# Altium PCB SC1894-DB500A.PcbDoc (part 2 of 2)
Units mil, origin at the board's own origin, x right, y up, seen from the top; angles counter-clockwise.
Board outline 1800 x 1000 mil, 4 copper layers (L1 TOP, L2 GND, L3 PWR, L4  BOT), stack 35.4 mil thick; 141 components, 89 nets, 320 pads, 589 vias.

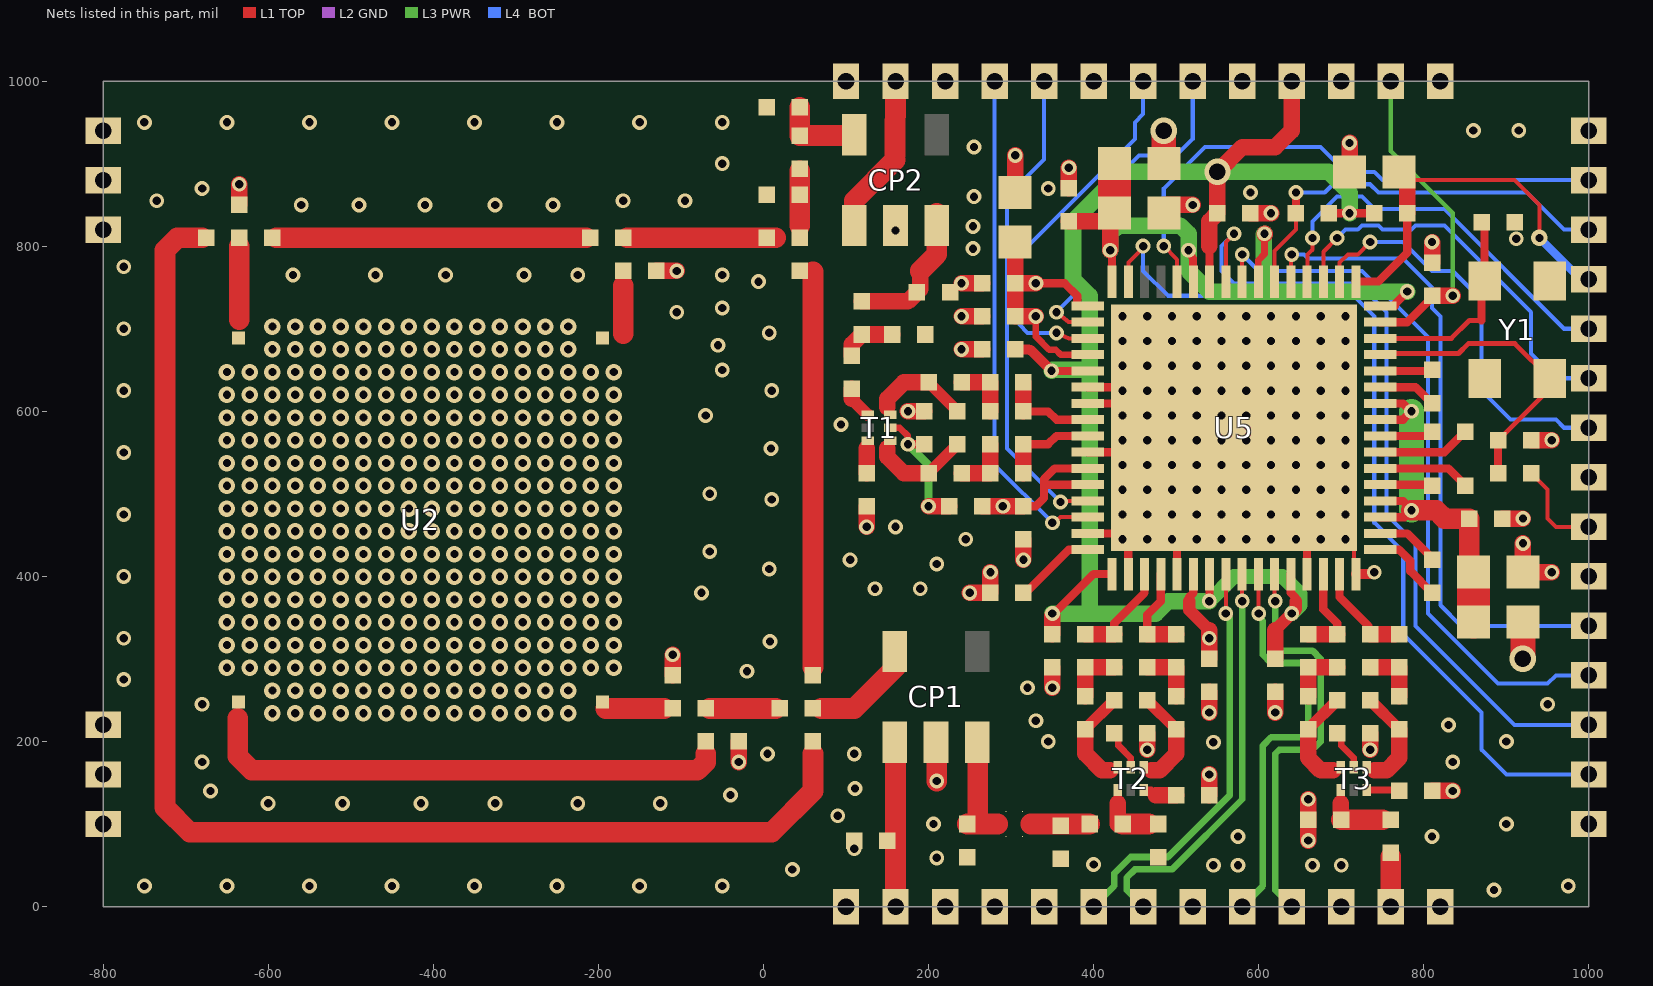
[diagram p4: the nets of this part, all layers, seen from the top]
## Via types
v1: diameter 20, hole 10, L1 TOP to L4  BOT, tented both sides, 308 vias
v2: diameter 18/18/18/18 (per signal layer), hole 10, L1 TOP to L4  BOT, tented both sides, 177 vias
v3: diameter 18/18/18/18 (per signal layer), hole 10, L1 TOP to L4  BOT, 100 vias
v4: diameter 32/32/32/32 (per signal layer), hole 20, L1 TOP to L4  BOT, tented both sides, 3 vias
v5: diameter 20/20/20/20 (per signal layer), hole 10, L1 TOP to L4  BOT, tented both sides, 1 vias

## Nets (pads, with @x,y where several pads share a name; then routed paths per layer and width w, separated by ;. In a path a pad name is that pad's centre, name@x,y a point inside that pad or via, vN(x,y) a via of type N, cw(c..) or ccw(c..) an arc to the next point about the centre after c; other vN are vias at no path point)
+1.8V: C6.1 C8.1 C9.1 C12.1 C31.1 C34.1 FT1.2 FT2.1 FT3.1 P30.1 U5.1 U5.4 U5.11 U5.12 U5.22 U5.47 | length 1125
  L1 TOP w5: C8.1@810,740 C8.1@812.05,740
  L1 TOP w8: v2(330,715) 330,690.58 346,674.58 354,674.58 360,668.58 U5.4@392.83,668.58
  L1 TOP w10: C31.1@315,485 330,485 340,495 340,511.1 ; v2(330,755) 365,755 380,740 380,727.64 U5.1@392.83,727.64 ; U5.12@392.83,511.1 340,511.1 ; U5.11@392.83,530.79 352.8,530.79 340,517.99 340,511.1 ; 515.79,370 515.79,375 520.79,380 U5.22@520.79,402.83 ; U5.47@747.17,707.95 780,707.95 C8.1@812.05,740
  L1 TOP w15: 515.79,370 515.79,359.21 540,335
  L1 TOP w20: FT3.1@265,485 v2(290,485) C31.1@315,485 ; C6.1@305,805 C9.1@305,755 ; v2(330,715) C12.1@305,715 C9.1@305,755 ; v2(330,755) C9.1@305,755 ; C34.1@540,300 v2(540,325) 540,335 ; C8.1@812.05,740 v2(835,740)
  L1 TOP w30: FT1.2@485,900 v4(485,940) ; v4(920,300) FT2.1@920,345
  L3 PWR w5: P30.1@760,1000 760,915 835,840 v2(835,740)
+3.3V: C3.2 C14.1 C33.1 C35.1 P32.1 R1.2 R2.1 U5.5 U5.17 U5.23 U5.28 U5.58 | length 2007.7
  L1 TOP w10: v2(349,649) 349.1,648.9 U5.5@392.83,648.9 ; v2@350,352.49 v2(350,355) 352.17,355 400,402.83 U5.17@422.36,402.83 ; v2(540,370) 540.47,370.47 U5.23@540.47,402.83 ; 540,800 540.47,799.53 U5.58@540.47,757.17 ; U5.28@638.9,402.83 638.9,380 645,373.9 645,370 ; R1.2@685,840 v2(710,840) R2.1@740,840
  L1 TOP w12: C14.1@305,675 321.34,675 322.17,674.17 323.83,674.17 v2(349,649)
  L1 TOP w15: 620,335 v2(640,355) 645,360 645,370
  L1 TOP w20: C33.1@350,330 v2@350,352.49 ; 540,800 540,830 C3.2@550,840 v4(550,890) 580,920 620,920 640,940 P32.1@640,1000 ; C35.1@620,300 620,335
  L3 PWR w18: v2(540,370) 570,400 628.75,400 650,378.75 650,365 v2(640,355)
  L3 PWR w20: v2(349,649) 350,650 395,650 ; v2(350,355) 395,355 ; v2(540,370) 490,370 475,355 395,355 ; v2(710,840) 710,865 685,890 v4(550,890) 435,890 375,830 375,760 395,740 395,650 ; 395,355 395,650
ADCIN0N: P7.1 U5.25 | length 495.6
  L1 TOP w5: U5.25@579.84,402.83 579.84,370 v2(580,370)
  L3 PWR w8: P7.1@460,0 440,20 440,35 450,45 495,45 580,130 v2(580,370)
ADCIN0P: P6.1 U5.24 | length 499.8
  L1 TOP w5: v2(560,355) 560.16,355 U5.24@560.16,402.83
  L3 PWR w8: P6.1@400,0 425,25 425,40 445,60 490,60 565,135 565,350 v2(560,355)
ADCIN1N: P10.1 U5.27 | length 504.3
  L1 TOP w5: U5.27@619.21,402.83 619.21,370 v2(620,370)
  L3 PWR w8: v2(620,370) 620,315 625,310 665,310 675,300 675,200 665,190 625,190 620,185 620,20 P10.1@640,0
ADCIN1P: P9.1 U5.26 | length 507.3
  L1 TOP w5: U5.26@599.53,402.83 599.53,355 v2(600,355)
  L3 PWR w8: P9.1@580,0 605,25 605,195 615,205 655,205 660,210 660,290 655,295 615,295 605,305 605,345 v2(600,355)
DGPIN0: P15.1 U5.63 | length 1104.3
  L1 TOP w5: U5.63@442.05,757.17 442.05,780 460,797.95 v2(460,800)
  L4  BOT w5: v2(460,800) 460,770 490,740 715,740 740,715 740,465 775,430 775,330 870,235 870,190 900,160 P15.1@1000,160
DGPIN1: P17.1 U5.56 | length 868.8
  L1 TOP w5: U5.56@579.84,757.17 579.84,790 v2(580,790)
  L4  BOT w5: v2(580,790) 600,770 725,770 805,690 805,355 890,270 950,270 960,280 P17.1@1000,280
EXTCLKIN: C15.2 P20.1 | length 117.4
  L1 TOP w5: C15.2@930,525 950,505 950,470 960,460 P20.1@1000,460
GND: C1.2 C2.1 C3.1 C4.2 C6.2 C8.2 C9.2 C10.2 C11.2 C12.2 C14.2 C26.1 C28.1 C29.2 C30.2 C31.2 C33.2 C34.2 C35.2 C36.2 C38.2 C40.2 C41.1 C45.2 C46.2 C47.2 CP1.2 CP2.2 P1.1 P3.1 P4.1 P5.1 P8.1 P11.1 P13.1 P14.1 P19.1 P21.1 P28.1 P29.1 P31.1 P33.1 P36.1 P39.1 P41.1 P42.1 P43.1 P44.1 P45.1 P46.1 P47.1 R12.1 R13.1 R15.1 R21.2 R23.2 R25.2 R27.2 R98.1 R99.1 R104.1 R105.1 U5.6 U5.7 U5.10 U5.15 U5.18 U5.21 U5.29 U5.32 U5.65 Y1.2 Y1.4 | length 2356.1
  L1 TOP w5: v3(705,445) 715.47,445 715.47,405 U5.32@717.64,402.83
  L1 TOP w10: U5.15@392.83,452.05 U5.65@442.05,452.05 ; U5.10@392.83,550.47 U5.65@442.05,550.47 ; U5.7@392.83,609.53 U5.65@570,609.53 ; U5.6@392.83,629.21 555,629.21 570,629.21 U5.65@570,609.53 ; U5.18@442.05,402.83 U5.65@442.05,452.05 ; U5.21@501.1,402.83 U5.65@501.1,452.05 ; U5.29@658.58,402.83 658.58,580 U5.65@570,580 ; U5.65@442.05,452.05 U5.65@501.1,452.05 ; U5.65@442.05,452.05 U5.65@442.05,550.47 ; U5.65@442.05,550.47 U5.65@501.1,550.47 ; U5.65@501.1,452.05 U5.65@501.1,550.47 ; U5.65@501.1,550.47 501.1,580 U5.65@570,580 ; U5.65@501.1,550.47 570,550.47 U5.65@570,580 ; U5.65@570,580 U5.65@570,609.53
  L1 TOP w12: U5.32@717.64,402.83 737.83,402.83 v2(740,405)
  L1 TOP w20: R98.1@-635,850 v2(-635,875) ; R105.1@-130,770 v2(-105,770) ; R104.1@-110,280 v2(-110,305) ; v2(-30,175) R99.1@-30,200 ; v2(125,460) C40.2@125,485 ; v2(175,600) C26.1@195,600 ; v2(240,675) C14.2@265,675 ; v2(240,715) C12.2@265,715 ; v2(240,755) C9.2@265,755 ; v2(250,380) R12.1@275,380 v2(275,405) ; C6.2@305,865 v2(305,910) ; v2(315,420) C31.2@315,445 ; v2(350,265) C33.2@350,290 ; C4.2@370,870 v2(370,895) ; v2(465,190) C28.1@465,210 ; C2.1@485,840 485,850 v2(520,850) ; C38.2@540,135 v2(540,160) ; v2(540,235) C34.2@540,260 ; C3.1@590,840 v2(615,840) ; v2(620,235) C35.2@620,260 ; v2(660,80) C45.2@660,105 v2(660,130) ; C1.2@710,890 v2(710,925) ; v2(735,190) C36.2@735,210 ; C41.1@810,140 v2(835,140) ; C8.2@810,780 v2(810,805) ; C29.2@895,470 v2(920,470) ; v2(920,440) C30.2@920,405 v2(955,405) ; C11.2@930,565 v2(955,565)
  L1 TOP w25: v2(210,152) CP1.2@210,210
  L2 GND w20: P1.1@100,0 100,1.81 P1.1@100.69,2.5 ; P3.1@219.7,2.5 220,2.2 P3.1@220,0 ; P31.1@700,999.24 P31.1@701.74,997.5 ; P13.1@820,2.33 P13.1@820.17,2.5
  L3 PWR w20: P1.1@100,0 100,1.94 P1.1@100.56,2.5 ; P3.1@220,0 P3.1@220,2.5
  other v1: -594.79,234.09 -567.23,234.09 -539.67,234.09 -512.11,234.09 -484.55,234.09 -456.99,234.09 -429.43,234.09 -401.87,234.09 -374.32,234.09 -346.76,234.09 -319.2,234.09 -291.64,234.09 -264.08,234.09 -236.52,234.09 -594.79,261.65 -567.23,261.65 -539.67,261.65 -512.11,261.65 -484.55,261.65 -456.99,261.65 -429.43,261.65 -401.87,261.65 -374.32,261.65 -346.76,261.65 -319.2,261.65 -291.64,261.65 -264.08,261.65 -236.52,261.65 -649.91,289.21 -622.35,289.21 -594.79,289.21 -567.23,289.21 -539.67,289.21 -512.11,289.21 -484.55,289.21 -456.99,289.21 -429.43,289.21 -401.87,289.21 -374.32,289.21 -346.76,289.21 -319.2,289.21 -291.64,289.21 -264.08,289.21 -236.52,289.21 -208.96,289.21 -181.4,289.21 -649.91,316.77 -622.35,316.77 -594.79,316.77 -567.23,316.77 -539.67,316.77 -512.11,316.77 -484.55,316.77 -456.99,316.77 -429.43,316.77 -401.87,316.77 -374.32,316.77 -346.76,316.77 -319.2,316.77 -291.64,316.77 -264.08,316.77 -236.52,316.77 -208.96,316.77 -181.4,316.77 -649.91,344.33 -622.35,344.33 -594.79,344.33 -567.23,344.33 -539.67,344.33 -512.11,344.33 -484.55,344.33 -456.99,344.33 -429.43,344.33 -401.87,344.33 -374.32,344.33 -346.76,344.33 -319.2,344.33 -291.64,344.33 -264.08,344.33 -236.52,344.33 -208.96,344.33 -181.4,344.33 -649.91,371.89 -622.35,371.89 -594.79,371.89 -567.23,371.89 -539.67,371.89 -512.11,371.89 -484.55,371.89 -456.99,371.89 -429.43,371.89 -401.87,371.89 -374.32,371.89 -346.76,371.89 -319.2,371.89 -291.64,371.89 -264.08,371.89 -236.52,371.89 -208.96,371.89 -181.4,371.89 -649.91,399.45 -622.35,399.45 -594.79,399.45 -567.23,399.45 -539.67,399.45 -512.11,399.45 -484.55,399.45 -456.99,399.45 -429.43,399.45 -401.87,399.45 -374.32,399.45 -346.76,399.45 -319.2,399.45 -291.64,399.45 -264.08,399.45 -236.52,399.45 -208.96,399.45 -181.4,399.45 -649.91,427.01 -622.35,427.01 -594.79,427.01 -567.23,427.01 -539.67,427.01 -512.11,427.01 -484.55,427.01 -456.99,427.01 -429.43,427.01 -401.87,427.01 -374.32,427.01 -346.76,427.01 -319.2,427.01 -291.64,427.01 -264.08,427.01 -236.52,427.01 -208.96,427.01 -181.4,427.01 -649.91,454.57 -622.35,454.57 -594.79,454.57 -567.23,454.57 -539.67,454.57 -512.11,454.57 -484.55,454.57 -456.99,454.57 -429.43,454.57 -401.87,454.57 -374.32,454.57 -346.76,454.57 -319.2,454.57 -291.64,454.57 -264.08,454.57 -236.52,454.57 -208.96,454.57 -181.4,454.57 -649.91,482.13 -622.35,482.13 -594.79,482.13 -567.23,482.13 -539.67,482.13 -512.11,482.13 -484.55,482.13 -456.99,482.13 -429.43,482.13 -401.87,482.13 -374.32,482.13 -346.76,482.13 -319.2,482.13 -291.64,482.13 -264.08,482.13 -236.52,482.13 -208.96,482.13 -181.4,482.13 -649.91,509.68 -622.35,509.68 -594.79,509.68 -567.23,509.68 -539.67,509.68 -512.11,509.68 -484.55,509.68 -456.99,509.68 -429.43,509.68 -401.87,509.68 -374.32,509.68 -346.76,509.68 -319.2,509.68 -291.64,509.68 -264.08,509.68 -236.52,509.68 -208.96,509.68 -181.4,509.68 -649.91,537.24 -622.35,537.24 -594.79,537.24 -567.23,537.24 -539.67,537.24 -512.11,537.24 -484.55,537.24 -456.99,537.24 -429.43,537.24 -401.87,537.24 -374.32,537.24 -346.76,537.24 -319.2,537.24 -291.64,537.24 -264.08,537.24 -236.52,537.24 -208.96,537.24 -181.4,537.24 -649.91,564.8 -622.35,564.8 -594.79,564.8 -567.23,564.8 -539.67,564.8 -512.11,564.8 -484.55,564.8 -456.99,564.8 -429.43,564.8 -401.87,564.8 -374.32,564.8 -346.76,564.8 -319.2,564.8 -291.64,564.8 -264.08,564.8 -236.52,564.8 -208.96,564.8 -181.4,564.8 -649.91,592.36 -622.35,592.36 -594.79,592.36 -567.23,592.36 -539.67,592.36 -512.11,592.36 -484.55,592.36 -456.99,592.36 -429.43,592.36 -401.87,592.36 -374.32,592.36 -346.76,592.36 -319.2,592.36 -291.64,592.36 -264.08,592.36 -236.52,592.36 -208.96,592.36 -181.4,592.36 -649.91,619.92 -622.35,619.92 -594.79,619.92 -567.23,619.92 -539.67,619.92 -512.11,619.92 -484.55,619.92 -456.99,619.92 -429.43,619.92 -401.87,619.92 -374.32,619.92 -346.76,619.92 -319.2,619.92 -291.64,619.92 -264.08,619.92 -236.52,619.92 -208.96,619.92 -181.4,619.92 -649.91,647.48 -622.35,647.48 -594.79,647.48 -567.23,647.48 -539.67,647.48 -512.11,647.48 -484.55,647.48 -456.99,647.48 -429.43,647.48 -401.87,647.48 -374.32,647.48 -346.76,647.48 -319.2,647.48 -291.64,647.48 -264.08,647.48 -236.52,647.48 -208.96,647.48 -181.4,647.48 -594.79,675.04 -567.23,675.04 -539.67,675.04 -512.11,675.04 -484.55,675.04 -456.99,675.04 -429.43,675.04 -401.87,675.04 -374.32,675.04 -346.76,675.04 -319.2,675.04 -291.64,675.04 -264.08,675.04 -236.52,675.04 -594.79,702.6 -567.23,702.6 -539.67,702.6 -512.11,702.6 -484.55,702.6 -456.99,702.6 -429.43,702.6 -401.87,702.6 -374.32,702.6 -346.76,702.6 -319.2,702.6 -291.64,702.6 -264.08,702.6 -236.52,702.6
  other v2: 885,20 -750,25 -650,25 -550,25 -450,25 -350,25 -250,25 -150,25 -50,25 975,25 35,45 545,50 575,50 665,50 700,50 400,51 210,59 110,70 575,85 810,85 206,100 900,100 90,110 -600,125 -510,125 -415,125 -325,125 -225,125 -125,125 -40,135 -670,140 111,143 -680,175 835,175 5,185 110,185 545,199 345,200 900,200 830,220 330,225 -680,245 950,245 320,265 -775,275 -20,285 8,321 -775,325 -75,380 135,385 190,385 -775,400 7,409 210,415 105,420 -65,430 245,445 160,460 -775,475 10,493 -65,500 -775,550 9,555 94,584 -70,595 -775,625 10,625 -50,650 -55,680 7,695 -775,700 -105,720 -50,725 -6,757 -570,765 -470,765 -385,765 -290,765 -225,765 -50,765 -775,775 254,797 912,809 160,819 254,824 -560,850 -490,850 -410,850 -325,850 -255,850 -735,855 -170,855 -95,855 255,860 590,865 -680,870 345,870 -50,900 255,920 860,940 915,940 -750,950 -650,950 -550,950 -450,950 -350,950 -250,950 -150,950 -50,950
  other v3: 435,445 465,445 495,445 525,445 555,445 585,445 615,445 645,445 675,445 435,475 465,475 495,475 525,475 555,475 585,475 615,475 645,475 675,475 705,475 435,505 465,505 495,505 525,505 555,505 585,505 615,505 645,505 675,505 705,505 435,535 465,535 495,535 525,535 555,535 585,535 615,535 645,535 675,535 705,535 435,565 465,565 495,565 525,565 555,565 585,565 615,565 645,565 675,565 705,565 435,595 465,595 495,595 525,595 555,595 585,595 615,595 645,595 675,595 705,595 435,625 465,625 495,625 525,625 555,625 585,625 615,625 645,625 675,625 705,625 435,655 465,655 495,655 525,655 555,655 585,655 615,655 645,655 675,655 705,655 435,685 465,685 495,685 525,685 555,685 585,685 615,685 645,685 675,685 705,685 435,715 465,715 495,715 525,715 555,715 585,715 615,715 645,715 675,715 705,715
LOADENB: P27.1 U5.60 | length 671.8
  L1 TOP w5: v2(485,800) 500.36,784.64 500.36,784.25 501.1,783.51 U5.60@501.1,757.17
  L4  BOT w5: v2(485,800) 485,870 535,920 675,920 705,890 740,890 750,880 P27.1@1000,880
MGPO0: P34.1 U5.2 | length 416.8
  L1 TOP w5: v2(355,720) 370,707.95 U5.2@392.83,707.95
  L4  BOT w5: v2(355,720) 380,745 380,835 455,910 500,910 520,930 P34.1@520,1000
MGPO1: P35.1 U5.3 | length 445.6
  L1 TOP w5: v2(355,695) 370,688.27 U5.3@392.83,688.27
  L4  BOT w5: v2(355,695) 320,695 310,705 310,790 450,930 450,950 460,960 P35.1@460,1000
MGPO2: P37.1 U5.13 | length 589.8
  L1 TOP w5: v2(360,490) 360,491.42 U5.13@392.83,491.42
  L4  BOT w5: P37.1@340,1000 340,905 295,860 295,555 v2(360,490)
MGPO3: P38.1 U5.14 | length 608.9
  L1 TOP w5: v2(350,465) 360,471.73 U5.14@392.83,471.73
  L4  BOT w5: P38.1@280,1000 280,535 v2(350,465)
N16778023: C11.1 C15.1 U5.45 Y1.3 | length 369.8
  L1 TOP w6: U5.45@747.17,668.58 747.17,670 842,670 854,682 910.32,682 Y1.3@952.37,639.94 952.37,627.37 C11.1@890,565
  L1 TOP w10: C15.1@890,525 C11.1@890,565
N16778042: C29.1 C30.1 FT2.2 U5.35 U5.36 U5.41 U5.42 | length 499.8
  L1 TOP w10: U5.35@747.17,471.73 776.73,471.73 v2(785,480) 785,481.42 775,491.42 U5.36@747.17,491.42 ; U5.41@747.17,589.84 775,589.84 775,590 v2(785,600) 784.53,600 775,609.53 U5.42@747.17,609.53
  L1 TOP w25: v2(785,480) 815,480 825,470 C29.1@855,470 855,400 C30.1@860,405
  L1 TOP w40: FT2.2@860,345 C30.1@860,405
  L3 PWR w30: v2(785,480) v2(785,600)
N16778055: C53.2 L2.2 U5.8 | length 117
  L1 TOP w10: C53.2@315,600 315.16,599.84 345,599.84 355,589.84 U5.8@392.83,589.84
  L1 TOP w20: C53.2@315,600 L2.2@315,635
N16778107: C52.2 L6.1 U5.20 | length 114.6
  L1 TOP w10: C52.2@465,330 465,353.58 481.42,370 U5.20@481.42,402.83
  L1 TOP w20: C52.2@465,330 L6.1@500,330
N16778109: C2.2 C4.1 FT1.1 U5.48 U5.55 U5.59 U5.64 | length 924.4
  L1 TOP w8: U5.55@599.53,757.17 599.53,783 607,790.47 v2@607,814.24
  L1 TOP w10: v2@420,802.36 420.98,795.13 421,795 422.36,785 U5.64@422.36,757.17 ; v2(515,795) 520.46,785.01 520.46,760.33 520.79,760 U5.59@520.79,757.17 ; U5.48@747.17,727.64 765,727.64 765,730 v2(780,745)
  L1 TOP w20: C4.1@370,830 C2.2@420,830 ; v2(420,795) 420,802.36 C2.2@420,830 ; C2.2@425,840 420,835 C2.2@420,830 ; FT1.1@425,895 FT1.1@425,900 ; v2@607,814.24 v2(607,815)
  L1 TOP w40: C2.2@425,840 FT1.1@425,895
  L3 PWR w20: v2(420,795) 420,815 430,825 505,825 515,815 v2(515,795) 515,769.99 539.99,744.99 ; v2(607,815) 606.29,814.29 606.29,744.99 ; v2(780,745) 775,745 606.29,744.99 ; 539.99,744.99 606.29,744.99 ; 540,744.99 606.29,744.99
N16778151: CP1.4 R11.2 R17.1 R101.1 | length 120.7
  L1 TOP w5: R17.1@60,240 70,240
  L1 TOP w25: 70,240 110,240 CP1.4@160,290
N16778208: C10.1 U5.46 Y1.1 | length 259.3
  L1 TOP w6: U5.46@747.17,688.27 833.27,688.27 855,710 870,710
  L1 TOP w10: 870,710 Y1.1@870,765 ; C10.1@870,829 873.63,825.37 Y1.1@873.63,758.06
N16778603: C26.2 FT3.2 T1.5 | length 165.7
  L1 TOP w8: T1.5@153.78,580 165,580 175,570 v2(175,560)
  L1 TOP w10: v2(175,560) C26.2@195,560
  L1 TOP w20: v2(200,485) FT3.2@225,485
  L3 PWR w10: v2(175,560) 200,535 v2(200,485)
N16778643: 
N16778760: R12.2 U5.16 | length 99.5
  L1 TOP w10: R12.2@315,380 317.64,380 370,432.36 U5.16@392.83,432.36
N16778848: L7.2 L8.1 U5.31 | length 123.2
  L1 TOP w10: U5.31@697.95,402.83 697.95,375 732.95,340 732.95,332.05 L7.2@735,330 ; L8.1@765,330 L8.1@770,330
  L1 TOP w20: L7.2@735,330 L8.1@765,330
N16778850: 
N16778878: L7.1 L9.2 U5.30 | length 114.8
  L1 TOP w10: U5.30@678.27,402.83 678.27,360 695,343.27 L7.1@695,330
  L1 TOP w20: L9.2@660,330 L7.1@695,330
N16778883: C39.1 C46.1 T2.1 | length 73.2
  L1 TOP w8: 429.25,125 T2.1@429.25,141.22
  L1 TOP w20: C39.1@429.25,100 429.25,125
  L1 TOP w25: C39.1@435,100 467,100
N16778942: C39.2 R22.1 R23.1 R24.1 | length 71
  L1 TOP w25: 324,100 C39.2@395,100
N16779024: C53.1 L3.1 U5.9 | length 117
  L1 TOP w10: C53.1@315,560 315.16,560.16 345,560.16 355,570.16 U5.9@392.83,570.16
  L1 TOP w20: L3.1@315,525 C53.1@315,560
N16779035: C52.1 L5.2 U5.19 | length 123
  L1 TOP w10: C52.1@425,330 425,343.27 461.73,380 U5.19@461.73,402.83
  L1 TOP w20: L5.2@390,330 C52.1@425,330
N16779391: C18.1 L5.1 L13.2 | length 70
  L1 TOP w20: L13.2@390,255 L5.1@390,290 C18.1@425,290
N16779395: C18.2 L6.2 L12.1 | length 70
  L1 TOP w20: C18.2@465,290 L6.2@500,290 L12.1@500,255
N16779627: C13.1 U5.44 | length 63.3
  L1 TOP w10: U5.44@747.17,648.9 808.9,648.9 C13.1@810,650
N16779631: C13.2 U5.43 | length 70.8
  L1 TOP w10: U5.43@747.17,629.21 790,629.21 809.21,610 C13.2@810,610
N16779697: C25.1 U5.40 | length 64.8
  L1 TOP w10: U5.40@747.17,570.16 805.16,570.16 C25.1@810,575
N16779756: C25.2 U5.39 | length 113
  L1 TOP w10: U5.39@747.17,550.47 825,550.47 849.53,575 C25.2@850,575
N16779783: C27.1 U5.38 | length 111.9
  L1 TOP w10: U5.38@747.17,530.79 830,530.79 850,510.79 C27.1@850,510
N16779793: C27.2 U5.37 | length 63.9
  L1 TOP w10: U5.37@747.17,511.1 810,511.1 C27.2@810,510
N16779834: C32.1 U5.34 | length 77.3
  L1 TOP w10: U5.34@747.17,452.05 780,452.05 810,422.05 C32.1@810,420
N16779938: C32.2 U5.33 | length 91.8
  L1 TOP w10: U5.33@747.17,432.36 770,432.36 783.68,418.68 783.68,406.32 C32.2@810,380
N16779945: 
N16780104: C20.1 L9.1 L11.2 | length 70
  L1 TOP w20: L11.2@660,255 L9.1@660,290 C20.1@695,290
N16780111: C20.2 L8.2 L10.1 | length 70
  L1 TOP w20: C20.2@735,290 L8.2@770,290 L10.1@770,255
N16780222: C17.1 L2.1 L14.2 | length 70
  L1 TOP w20: L14.2@240,635 L2.1@275,635 C17.1@275,600
N16780244: C17.2 L3.2 L15.1 | length 70
  L1 TOP w20: L15.1@240,525 L3.2@275,525 C17.2@275,560
N16798679: R102.2 R105.2 U2.2 | length 76
  L1 TOP w5: -170,752 R105.2@-170,770
  L1 TOP w25: -170,694 -170,752
N16798683: R97.1 R104.2 U2.1 | length 81
  L1 TOP w5: R97.1@-120,240 R97.1@-110,240
  L1 TOP w25: U2.1@-191,240 R97.1@-120,240
N16798687: R96.1 R99.2 U2.4 | length 649.2
  L1 TOP w5: -70,185 R99.2@-70,200
  L1 TOP w25: -637,228 -637,182 -620,165 -80,165 -70,175 -70,185
N16798691: R95.2 R98.2 R100.2 U2.3 | length 99
  L1 TOP w5: R98.2@-635,800 R98.2@-635,810
  L1 TOP w25: -635,711 R98.2@-635,800
N16798746: R8.2 R102.1 R103.1 | length 190
  L1 TOP w5: R103.1@-170,810 R103.1@-165,810 ; 15,810 20,810
  L1 TOP w25: R103.1@-165,810 R8.2@4,810 15,810
N16798748: R8.1 R9.2 R14.1 R15.2 | length 66
  L1 TOP w25: 44,825 R14.1@44,891
N16798750: R100.1 R103.2 | length 385
  L1 TOP w5: R100.1@-595,810 R100.1@-590,810 ; R103.2@-215,810 R103.2@-210,810
  L1 TOP w25: R100.1@-590,810 R103.2@-215,810
N16798758: R17.2 R96.2 R97.2 | length 95.7
  L1 TOP w5: R97.2@-72.68,235 R97.2@-70,240 R97.2@-65,240 ; R17.2@15,240 R17.2@20,240
  L1 TOP w25: R97.2@-65,240 R17.2@15,240
N16798802: R95.1 R101.2 | length 1609.4
  L1 TOP w5: R95.1@-680,810 R95.1@-675,810 ; 60,185 R101.2@60,200
  L1 TOP w25: R95.1@-680,810 -710,810 -725,795 -725,120 -695,90 10,90 60,140 60,185
N16798852: R9.1 R11.1 | length 507.1
  L1 TOP w3.94: R9.1@44,770 49,765 60,765
  L1 TOP w5: R11.1@60,280 60,290
  L1 TOP w25: 60,290 60,765 60,769
N16798884: 
N16798892: 
N16798938: 
N16809609: C21.1 L11.1 T3.6 | length 131.5
  L1 TOP w5: 690,165 695,165 698.78,168.78 T3.6@699.25,168.78
  L1 TOP w14: L11.1@660,215 C21.1@695,250
  L1 TOP w20: L11.1@660,215 660,180 675,165 690,165
N16810438: C21.2 L10.2 T3.4 | length 131.5
  L1 TOP w5: T3.4@730.75,168.78 731.22,168.78 735,165 740,165
  L1 TOP w14: C21.2@735,250 L10.2@770,215
  L1 TOP w20: 740,165 755,165 770,180 L10.2@770,215
N16818333: C36.1 T3.5 | length 52.4
  L1 TOP w8: C36.1@695,210 700,210 700,195 715,180 T3.5@715,168.78
N16820786: C42.2 C45.1 T3.1 | length 97
  L1 TOP w5: C42.2@750,105 C42.2@760,105
  L1 TOP w8: C45.1@699.25,105 C45.1@700,105 ; 699.25,125 T3.1@699.25,141.22
  L1 TOP w20: C45.1@699.25,105 699.25,125
  L1 TOP w25: C45.1@700,105 C42.2@750,105
N16837562: C19.1 L13.1 T2.6 | length 128.6
  L1 TOP w5: 420,165 425.47,165 T2.6@429.25,168.78
  L1 TOP w14: L13.1@390,215 C19.1@425,250
  L1 TOP w20: L13.1@390,215 390,185 410,165 420,165
N16837983: C19.2 L12.2 T2.4 | length 128.6
  L1 TOP w5: T2.4@460.75,168.78 464.53,165 470,165
  L1 TOP w14: C19.2@465,250 L12.2@500,215
  L1 TOP w20: 470,165 480,165 500,185 L12.2@500,215
N16842500: C28.2 T2.5 | length 52.4
  L1 TOP w8: C28.2@425,210 430,210 430,195 445,180 T2.5@445,168.78
N16852193: C23.1 L14.1 T1.6 | length 128.6
  L1 TOP w5: 150,605 150,599.53 T1.6@153.78,595.75
  L1 TOP w14: L14.1@200,635 C23.1@235,600
  L1 TOP w20: 150,605 150,615 170,635 L14.1@200,635
N16853064: C23.2 L15.2 T1.4 | length 128.6
  L1 TOP w5: 150,555 150,560.47 T1.4@153.78,564.25
  L1 TOP w14: L15.2@200,525 C23.2@235,560
  L1 TOP w20: 150,555 150,545 170,525 L15.2@200,525
N16864474: 
N16886954: CP2.1 R26.2 R27.1 | length 177.5
  L1 TOP w20: R26.2@119,733 175,733 R27.1@186,744 190,748 190,770
  L1 TOP w25: 190,770 210,790 CP2.1@210,825 CP2.1@210,840
N16887872: 
N16905362: C41.2 T3.3 | length 39.8
  L1 TOP w8: T3.3@730.75,141.22 768.78,141.22 C41.2@770,140
N16905883: C38.1 T2.3 | length 42.5
  L1 TOP w8: T2.3@460.75,141.22 470,141.22 470,140 475,135
  L1 TOP w20: 475,135 C38.1@500,135
N16907208: C40.1 T1.3 | length 39.8
  L1 TOP w5: 125,555 126.22,556.22 T1.3@126.22,564.25
  L1 TOP w20: C40.1@125,525 125,555
RESETN: C1.1 P25.1 R2.2 U5.49 | length 483.1
  L1 TOP w5: C1.1@775.6,880 780,880 910,880 940,850 v5(940,810)
  L1 TOP w10: U5.49@717.64,757.17 745,757.17 780,792.17 R2.2@780,833.6 ; C1.1@770,890 C1.1@775.6,880
  L1 TOP w20: C1.1@775.6,880 776.8,887.2 780,884 780,880 R2.2@780,840
  L4  BOT w10: v5(940,810) 990,760 P25.1@1000,760
RFFB: C42.1 P12.1 | length 65
  L1 TOP w5: C42.1@760,60 C42.1@760,65
  L1 TOP w25: P12.1@760,0 C42.1@760,60
RFIN: C47.1 CP1.3 P2.1 | length 209
  L1 TOP w25: P2.1@160,0 CP1.3@160,209
RFIN_CPL_CPL: CP1.1 R21.1 R22.0 R24.0 | length 142.1
  L1 TOP w3.94: R21.1@247,100 259.5,112.5 ; CP1.1@259,199 259.5,198.5 CP1.1@260,198
  L1 TOP w25: R21.1@247,100 284,100 ; 259.5,112.5 CP1.1@259.5,198.5
RFOUT: CP2.3 P40.1 | length 185.5
  L1 TOP w3.94: 159.37,904.37 159.37,910
  L1 TOP w25: CP2.3@110,835 110,855 159.37,904.37 ; 159.37,910 P40.1@160,1000
RFOUT_BLN_SE: C43.1 T1.1 | length 39.2
  L1 TOP w15: 107,614.97 T1.1@126.22,595.75
  L1 TOP w20: 107,614.97 C43.1@107,627
RFOUT_BLN_SE_DCBL: C43.2 R25.1 R26.1 | length 68
  L1 TOP w20: C43.2@107,667 107,681 R26.1@119,693 R25.1@156,693
RFOUT_CPL_IN: CP2.4 R13.2 R14.2 | length 100.4
  L1 TOP w3.94: CP2.4@109,934 CP2.4@110,935
  L1 TOP w25: R13.2@44,968 R14.2@44,934 CP2.4@109,934
SCLK: P23.1 U5.51 | length 481
  L1 TOP w5: U5.51@678.27,757.17 678.27,793.27 v2(695,810)
  L4  BOT w5: v2(695,810) 705,820 720,820 725,825 745,825 750,820 785,820 790,825 825,825 930,720 930,670 960,640 P23.1@1000,640
SDI: P18.1 U5.53 | length 800
  L1 TOP w5: U5.53@638.9,757.17 638.9,790 v2(640,790)
  L4  BOT w5: v2(640,790) 655,790 660,785 775,785 810,750 810,725 820,715 820,365 845,340 P18.1@1000,340
SDO: P26.1 R1.1 U5.54 | length 500.4
  L1 TOP w5: U5.54@619.21,757.17 619.21,794.21 645,820 R1.1@645,840
  L1 TOP w10: R1.1@645,840 v2(645,865)
  L4  BOT w5: v2(645,865) 680,865 690,875 735,875 745,865 925,865 970,820 P26.1@1000,820
SSN: P24.1 U5.52 | length 489.2
  L1 TOP w5: U5.52@658.58,757.17 658.58,760 659.29,760.71 659.29,790 665,795.71 v2(665,810)
  L4  BOT w5: v2(665,810) 665,830 695,860 725,860 740,845 825,845 970,700 P24.1@1000,700
STATO: P16.1 U5.57 | length 988
  L1 TOP w5: U5.57@560.16,757.17 560.16,805 570,814.84 v2(570,815)
  L4  BOT w5: v2(570,815) 555,800 555,770 570,755 720,755 755,720 755,475 790,440 790,340 910,220 P16.1@1000,220
WDTENB: P22.1 U5.50 | length 492.9
  L1 TOP w5: U5.50@697.95,757.17 697.95,780 707.95,790 720,790 v2(735,805)
  L4  BOT w5: v2(735,805) 775,805 810,770 835,770 870,735 870,625 905,590 960,590 970,580 P22.1@1000,580
pads on no net: CP1.6 CP2.6 T1.2 T2.2 T3.2 U5.61 U5.62

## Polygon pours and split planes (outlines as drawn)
GND on L3 PWR "L3 PWR-GND" (solid, remove dead copper, pour order 4): -790,990 250,990 250,260 990,260 990,10 -790,10
+1.8V on L3 PWR "L3 PWR-+1.8V" (solid, remove dead copper, pour order 2): 260,990 990,990 990,270 260,270
GND on L1 TOP "L1 TOP-GND" (solid, remove dead copper, pour order 6): -790,990 990,990 990,10 -790,10
GND on L4  BOT "L4  BOT-GND" (solid, remove dead copper, pour order 8): -790,990 990,990 990,10 -790,10
GND on L2 GND "L2 GND-GND" (solid, remove dead copper, pour order 10): -790,990 990,990 990,10 -790,10

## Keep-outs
Keep-Out Layer:
  the board outline again, w1

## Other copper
L1 TOP:
  rectangle net N16798687: -644,225 -628,256
  rectangle net N16798679: -203,681 -158,697
  rectangle net N16798691: -644,681 -628,720
  rectangle net RFIN_CPL_CPL: 286,80 299,120
  rectangle net N16778942: 309,80 322,120
  rectangle net GND: 186,666 248,711
  region net GND: -616,669 -616,697 -589,697 -589,725 -215,725 -215,669 -187,669 -187,653 -155,653 -155,278 -187,278 -187,268 -215,268 -215,234.09 -616,234.09 -616,268 -670,268 -670,669
  region net GND: 111,980 89,980 89,1000 111,1000
  region net GND: 831,965 809,965 809,1000 831,1000 831,965
  region net GND: 231,980 209,980 209,1000 231,1000
  region net GND: 711,965 689,965 689,1000 711,1000 711,965
  region net GND: 831,0 809,0 809,35 831,35 831,0
  region net GND: 1000,951 1000,929 965,929 965,951 1000,951
  region net GND: 411,965 389,965 389,1000 411,1000 411,965
  region net GND: -765,951 -765,929 -800,929 -800,951 -765,951
  region net GND: 1000,411 1000,389 965,389 965,411 1000,411
  region net GND: -765,831 -765,809 -800,809 -800,831 -765,831
  region net GND: 591,965 569,965 569,1000 591,1000 591,965
  region net GND: 231,0 209,0 209,35 231,35 231,0
  region net GND: 711,0 689,0 689,35 711,35 711,0
  region net GND: 111,0 89,0 89,35 111,35 111,0
  region net GND: -765,111 -765,89 -800,89 -800,111 -765,111
  region net GND: -765,891 -765,869 -800,869 -800,891 -765,891
  region net GND: 351,0 329,0 329,35 351,35 351,0
  region net GND: 291,0 269,0 269,35 291,35 291,0
  region net GND: 1000,531 1000,509 965,509 965,531 1000,531
  region net GND: 1000,111 1000,89 965,89 965,111 1000,111
  region net GND: -765,231 -765,209 -800,209 -800,231 -765,231
  region net GND: -765,171 -765,149 -800,149 -800,171 -765,171
  region net GND: 531,0 509,0 509,35 531,35 531,0
  text "L1 TOP" at -848,-767 h50
L2 GND:
  region net GND: 965,929 965,951 1000,951 1000,929 965,929
  region net GND: 965,389 965,411 1000,411 1000,389 965,389
  region net GND: -800,209 -800,231 -765,231 -765,209 -800,209
  region net GND: 711,965 689,965 689,1000 711,1000 711,965
  region net GND: 231,965 209,965 209,1000 231,1000 231,965
  region net GND: -800,929 -800,951 -765,951 -765,929 -800,929
  region net GND: 711,0 689,0 689,35 711,35 711,0
  region net GND: 831,0 809,0 809,35 831,35 831,0
  region net GND: -800,149 -800,171 -765,171 -765,149 -800,149
  region net GND: 591,965 569,965 569,1000 591,1000 591,965
  region net GND: 531,0 509,0 509,35 531,35 531,0
  region net GND: 831,965 809,965 809,1000 831,1000 831,965
  region net GND: 965,89 965,111 1000,111 1000,89 965,89
  region net GND: 291,0 269,0 269,35 291,35 291,0
  region net GND: 111,965 89,965 89,1000 111,1000 111,965
  region net GND: 111,0 89,0 89,35 111,35 111,0
  region net GND: -800,89 -800,111 -765,111 -765,89 -800,89
  region net GND: 1000,531 1000,509 965,509 965,531 1000,531
  region net GND: -800,869 -800,891 -765,891 -765,869 -800,869
  region net GND: 231,0 209,0 209,35 231,35 231,0
  region net GND: -800,809 -800,831 -765,831 -765,809 -800,809
  region net GND: 351,0 329,0 329,35 351,35 351,0
  region net GND: 411,965 389,965 389,1000 411,1000 411,965
  region net GND: -616,669 -616,725 -215,725 -215,669 -155,669 -155,268 -215,268 -215,208 -616,208 -616,268 -670,268 -670,669
  text "L2 GND" at -848,-767 h50
L3 PWR:
  region net GND: -800,89 -800,111 -765,111 -765,89 -800,89
  region net GND: 209,1000 231,1000 231,965 209,965 209,1000
  region net GND: 89,1000 111,1000 111,965 89,965 89,1000
  region net +1.8V: 744,1000 776,1000 776,945 744,945 744,1000
  region net GND: -800,209 -800,231 -765,231 -765,209 -800,209
  region net GND: -800,929 -800,951 -765,951 -765,929 -800,929
  region net GND: 89,35 111,35 111,0 89,0 89,35
  region net GND: 329,35 351,35 351,0 329,0 329,35
  region net GND: -800,149 -800,171 -765,171 -765,149 -800,149
  region net GND: -800,869 -800,891 -765,891 -765,869 -800,869
  region net GND: 209,35 231,35 231,0 209,0 209,35
  region net GND: 965,89 965,111 1000,111 1000,89 965,89
  region net GND: 269,35 291,35 291,0 269,0 269,35
  region net GND: -800,809 -800,831 -765,831 -765,809 -800,809
  region net GND: 809,35 831,35 831,0 809,0 809,35
  region net GND: 689,35 711,35 711,0 689,0 689,35
  region net GND: 509,35 531,35 531,0 509,0 509,35
  region net GND: -616,669 -616,725 -215,725 -215,669 -155,669 -155,268 -215,268 -215,208 -616,208 -616,268 -670,268 -670,669
  text "L3 PWR" at -848,-767 h50
L4  BOT:
  region net GND: 804,35 836,35 836,0 804,0 804,35
  region net GND: 965,924 965,956 1000,956 1000,924 965,924
  region net GND: 965,84 965,116 1000,116 1000,84 965,84
  region net GND: -800,144 -800,176 -765,176 -765,144 -800,144
  region net GND: 564,1000 596,1000 596,965 564,965 564,1000
  region net GND: 264,35 296,35 296,0 264,0 264,35
  region net GND: 84,35 116,35 116,0 84,0 84,35
  region net GND: 965,504 965,536 1000,536 1000,504 965,504
  region net GND: -800,204 -800,236 -765,236 -765,204 -800,204
  region net GND: -800,804 -800,836 -765,836 -765,804 -800,804
  region net GND: -800,864 -800,896 -765,896 -765,864 -800,864
  region net GND: 204,35 236,35 236,0 204,0 204,35
  region net GND: 84,1000 116,1000 116,965 84,965 84,1000
  region net GND: 684,35 716,35 716,0 684,0 684,35
  region net GND: 204,1000 236,1000 236,965 204,965 204,1000
  region net GND: 684,1000 716,1000 716,965 684,965 684,1000
  region net GND: 504,35 536,35 536,0 504,0 504,35
  region net GND: 384,1000 416,1000 416,965 384,965 384,1000
  region net GND: 324,35 356,35 356,0 324,0 324,35
  region net GND: -800,84 -800,116 -765,116 -765,84 -800,84
  region net GND: -800,924 -800,956 -765,956 -765,924 -800,924
  region net GND: 804,1000 836,1000 836,965 804,965 804,1000
  region net GND: 965,384 965,416 1000,416 1000,384 965,384
  region net GND: -612.03,674.02 -612.03,730.02 -211.03,730.02 -211.03,674.02 -151.03,674.02 -151.03,273.02 -211.03,273.02 -211.03,213.02 -612.03,213.02 -612.03,273.02 -666.03,273.02 -666.03,674.02
  text "RDB3.1 REV3" at -725,365 h25 r270
  text "L4 BOT" at -848,-767 h50
Multi-Layer:
  text "SCINTERA" at -874,-316 h50
  text "SC1894-DB500A   ASSEMBLY DRAWING" at -874,-466 h50
  text "(RDB3.1 REV3)" at -890,-623 h50

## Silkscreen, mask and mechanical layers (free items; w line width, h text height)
Silkscreen Top:
  region: 840,265 960,265 960,40 840,40 840,265
  region: 80,60 120,60 100,30 80,60
  text "SCINTERA" at -610,905 h25
  text "RDB3.1 REV3" at -385,905 h25
  text "SILK TOP" at -848,-767 h50
Paste Mask Top:
  text "PASTE TOP" at -848,-767 h50
Solder Mask Top:
  rectangle: 306,77 327,123
  rectangle: 280,77 302,123
  region: -565,840 -240,840 -240,780 -565,780 -565,840
  region: 40,180 85,180 85,130 15,60 -705,60 -750,105 -750,805 -720,835 -695,835 -695,135 -680,120 5,120 40,155 40,180
  region: -120,840 -120,785 5,785 5,840 -120,840
  region: 35,745 80,745 80,305 35,305 35,745
  region: -95,195 -95,140 -660,140 -660,195 -95,195
  text "SOLDERMASK TOP" at -848,-767 h50
Solder Mask Bottom:
  region: 650,575 715,575 715,510 650,510 650,575
  region: 500,500 565,500 565,435 500,435 500,500
  region: 650,650 715,650 715,585 650,585 650,650
  region: 425,575 490,575 490,510 425,510 425,575
  region: 575,650 640,650 640,585 575,585 575,650
  region: 650,500 715,500 715,435 650,435 650,500
  region: 575,575 640,575 640,510 575,510 575,575
  region: 575,725 640,725 640,660 575,660 575,725
  region: 425,500 490,500 490,435 425,435 425,500
  region: 425,650 490,650 490,585 425,585 425,650
  region: 425,725 490,725 490,660 425,660 425,725
  region: 500,725 565,725 565,660 500,660 500,725
  region: 500,575 565,575 565,510 500,510 500,575
  region: 500,650 565,650 565,585 500,585 500,650
  region: 575,500 640,500 640,435 575,435 575,500
  region: 650,725 715,725 715,660 650,660 650,725
  text "SOLDERMASK BOT" at -848,-767 h50
Assembly Drawing Top:
  lines w5: -558.12,1369.08 -77.42,1369.08 ; -552.74,1378.04 -93.99,1378.04 ; -547.37,1387 -305,1387 ; -541.99,1395.96 -314.41,1395.96 ; -537.06,1404.92 -378.47,1404.92 ; -532.14,1413.88 -387.43,1413.88 ; -527.21,1422.84 -396.39,1422.84 ; -521.83,1431.8 -405.8,1431.8 ; -516.46,1440.76 -406.7,1440.76 ; -511.08,1449.72 -407.59,1449.72 ; -506.6,1458.68 -408.94,1458.68 ; -500.78,1467.64 -409.83,1467.64 ; -495.85,1476.6 -410.73,1476.6 ; -491.37,1485.56 -411.62,1485.56 ; -485.99,1494.52 -412.97,1494.52 ; -481.06,1503.48 -414.31,1503.48 ; -475.24,1512.44 -415.66,1512.44 ; -470.31,1521.4 -416.55,1521.4 ; -465.38,1530.36 -411.62,1530.36 ; -460.01,1539.32 -407.59,1539.32 ; -454.63,1548.28 -415.66,1548.28 ; -449.26,1557.24 -431.78,1557.24 ; -434.92,1584.12 -379.37,1584.12 ; -429.54,1593.08 -372.2,1593.08 ; -424.62,1602.04 -366.38,1602.04 ; -423.27,1575.16 -385.64,1575.16 ; -419.24,1611 -360.1,1611 ; -414.31,1619.96 -351.14,1619.96 ; -408.94,1628.92 -341.29,1628.92 ; -406.25,1566.2 -391.46,1566.2 ; -404.9,1543.35 -416.1,1520.95 -404.9,1431.35 -371.3,1397.75 -360.1,1397.75 ccw(c-365.95,1414.55) -360.1,1431.35 -371.3,1509.75 -360.55,1519.16 ; -403.56,1637.88 -312.17,1637.88 ; -399.08,1646.84 -263.34,1646.84 ; -395.05,1560.82 -360.1,1610.55 -337.7,1632.95 -214.5,1655.35 ; -393.7,1655.8 -214.5,1655.8 ; -388.78,1664.76 -219.43,1664.76 ; -383.4,1673.72 -224.36,1673.72 ; -378.92,1682.68 -229.74,1682.68 ; -373.54,1691.64 -235.11,1691.64 ; -368.17,1700.6 -239.59,1700.6 ; -362.79,1709.56 -245.42,1709.56 ; -361.45,1440.76 -356.97,1440.76 ; -360.1,1431.8 -339.5,1431.8 ; -360.1,1442.55 -315.3,1420.15 ; -357.86,1718.52 -249.9,1718.52 ; -352.94,1727.48 -255.72,1727.48 ; -351.14,1404.92 -317.99,1404.92 ; -350.25,1422.84 -320.23,1422.84 ; -348.46,1413.88 -318.44,1413.88 ; -347.56,1736.44 -260.65,1736.44 ; -345.32,1533.94 -315.3,1543.35 -270.5,1498.55 ; -342.63,1745.4 -265.13,1745.4 ; -337.26,1754.36 -271.4,1754.36 ; -332.33,1763.32 -276.33,1763.32 ; -330.09,1502.14 -330.09,1468.54 -296.49,1446.14 ; -326.95,1772.28 -281.26,1772.28 ; -322.02,1781.24 -287.08,1781.24 ; -316.65,1790.2 -291.56,1790.2 ; -311.27,1799.16 -296.04,1799.16 ; -306.34,1808.12 -301.42,1808.12 ; -304.55,1387 -111.02,1387 ; -294.7,1395.96 -127.14,1395.96 ; -285.74,1404.92 -145.06,1404.92 ; -281.7,1408.95 -259.3,1408.95 ccw(c-269.99,1412.82) -265.58,1423.29 ; -281.26,1476.6 -281.7,1476.6 -304.1,1431.35 ccw(c-292.89,1408.95) -304.11,1386.55 -236.9,1453.75 ; -270.95,1494.97 -270.95,1498.55 ; -263.34,1422.84 -179.56,1422.84 ; -259.3,1431.35 -236.9,1431.35 ccw(c-249.11,1431.94) -244.97,1443.45 ; -257.96,1413.88 -161.19,1413.88 ; -240.94,1440.76 -213.16,1440.76 ; -240.94,1449.72 -229.29,1449.72 ; -236.46,1431.8 -195.24,1431.8 ; -222.12,1468.09 -214.5,1476.15 -192.1,1543.35 -165.22,1569.34 ; -219.43,1467.64 -106.09,1467.64 ; -214.5,1476.6 -111.91,1476.6 ; -211.37,1485.56 -116.39,1485.56 ; -208.23,1494.52 -121.77,1494.52 ; -205.1,1503.48 -127.14,1503.48 ; -202.86,1458.68 -101.16,1458.68 ; -201.96,1512.44 -132.07,1512.44 ; -199.27,1521.4 -137,1521.4 ; -195.69,1530.36 -142.82,1530.36 ; -193,1539.32 -148.2,1539.32 ; -186.28,1449.72 -96.23,1449.72 ; -186.28,1548.28 -153.13,1548.28 ; -177.32,1557.24 -157.61,1557.24 ; -168.81,1440.76 -90.41,1440.76 ; -168.36,1566.2 -162.98,1566.2 ; -152.68,1431.8 -85.03,1431.8 ; -136.1,1422.84 -81,1422.84 ; -119.53,1413.88 -76.07,1413.88 ; -102.06,1404.92 -70.7,1404.92 ; -85.48,1395.96 -65.32,1395.96 ; -68.01,1387 -59.5,1387 ; -561.26,1363.7 -445.67,1564.41 -66.22,1363.7 -561.26,1363.7 ; -436.26,1581.88 -55.91,1380.28 -304.1,1812.6 -436.26,1581.88
  text "ALL PROCESSES MUST BE ROHS COMPLIANT." at -665,1990 h60
  text "CAUTION" at 520,1787 h60
  text "THIS ASSEMBLY INCORPORATES" at 345,1712 h30
  text "STATIC SENSITIVE DEVICES" at 420,1637 h30
  text "ASSEMBLY AND HANDLING MUST BE DONE AT AN" at 145,1562 h30
  text "APPROVED STATIC FREE STATION" at 370,1487 h30
  text "CAUTION" at 545,1362 h60
  text "GND" at 110,1070 h20 r90
  text "RFOUT" at 170,1070 h20 r90
  text "GND" at 230,1070 h20 r90
  text "MGPO3" at 300,1070 h20 r90
  text "MGPO2" at 360,1070 h20 r90
  text "GND" at 420,1070 h20 r90
  text "MGPO1" at 480,1070 h20 r90
  text "MGPO0" at 540,1070 h20 r90
  text "GND" at 595,1070 h20 r90
  text "+3.3V" at 650,1070 h20 r90
  text "GND" at 710,1070 h20 r90
  text "+1.8V" at 770,1070 h20 r90
  text "GND" at 830,1070 h20 r90
  text "GND" at -945,930 h20
  text "GND" at 1115,930 h20
  text "GND" at -945,870 h20
  text "LOADENB" at 1115,870 h20
  text "GND" at -945,810 h20
  text "SDO" at 1115,810 h20
  text "RESETN" at 1115,745 h20
  text "SSN" at 1115,690 h20
  text "SCLK" at 1115,630 h20
  text "WDTENB" at 1115,570 h20
  text "GND" at 1115,510 h20
  text "EXTCLKIN" at 1115,445 h20
  text "GND" at 1115,385 h20
  text "SDI" at 1115,325 h20
  text "DGPIN1" at 1115,270 h20
  text "STATO" at 1120,210 h20
  text "GND" at -940,205 h20
  text "DGPIN0" at 1115,155 h20
  text "GND" at -940,145 h20
  text "GND" at 1120,90 h20
  text "GND" at -940,85 h20
  text "GND" at 110,-170 h20 r90
  text "RFIN" at 170,-170 h20 r90
  text "GND" at 230,-170 h20 r90
  text "GND" at 295,-170 h20 r90
  text "GND" at 355,-170 h20 r90
  text "ADCIN0P" at 415,-170 h20 r90
  text "ADCIN0N" at 475,-170 h20 r90
  text "GND" at 530,-170 h20 r90
  text "ADCIN1P" at 590,-170 h20 r90
  text "ADCIN1N" at 650,-170 h20 r90
  text "GND" at 710,-170 h20 r90
  text "RFFB" at 770,-170 h20 r90
  text "GND" at 830,-170 h20 r90
  text "ASSY TOP" at -198,-767 h50
Drill Drawing:
  lines w1: -800,1050 -799.97,1050 ; -800,1100 -800,1240 ; -76.59,1190 -800,1190 ; 276.59,1190 1000,1190 ; 985,1000 985.03,1000 ; 1000,0 1000.03,0 ; 1000,1045 1000.03,1045 ; 1000,1095 1000,1240 ; 1035,1000 1290,1000 ; 1050,0 1290,0 ; 1240,432.5 1240,0 ; 1240,567.5 1240,1000 ; 2690,-1310 2690.03,-1310 ; 2700,-380 2700.03,-380 ; -800,1190 -700,1165 -700,1215 -800,1190 ; 1000,1190 900,1215 900,1165 1000,1190 ; 1240,0 1265,100 1215,100 1240,0 ; 1240,1000 1215,900 1265,900 1240,1000 ; 2740,-1310 2740,-1260 4690,-1260 4690,-1310 2740,-1310 ; 2740,-1010 2740,-960 4690,-960 4690,-1010 2740,-1010 ; 2740,-710 2740,-660 4690,-660 4690,-710 2740,-710 ; 2740,-410 2740,-360 4690,-360 4690,-410 2740,-410 ; 2840,-1260 2840,-1010 4590,-1010 4590,-1260 2840,-1260 ; 2840,-960 2840,-710 4590,-710 4590,-960 2840,-960 ; 2840,-660 2840,-410 4590,-410 4590,-660 2840,-660
  lines w10: 2259,-1310 2640,-1310 ; 2259,-380 2650,-380 ; 2309,-1460 2309,-1310 ; 2309,-230 2309,-380 ; 2309,-1310 2284,-1410 2334,-1410 2309,-1310 ; 2309,-380 2334,-280 2284,-280 2309,-380
  text "NOTES: (UNLESS OTHERWISE SPECIFIED)" at 2210,3075 h60
  text "1) FINISHED BOARD THICKNESS TO BE 42 MILS +/- 10%." at 2190,2790 h50
  text "2) SOLDERMASK TO BE LPI, COLOR : GREEN, BOTH SIDES." at 2190,2640 h50
  text "3) PLATING:  IMMERSION GOLD OVER ELECTROLESS NICKEL." at 2190,2490 h50
  text "- ALL LAYERS USE 1 OZ COPPER." at 2340,2340 h50
  text "4) SILKSCREEN:  TOP SIDE, COLOR: WHITE" at 2190,2190 h50
  text "5) SEE DRILL CHART FOR FINISHED HOLE SIZES." at 2190,2040 h50
  text "6) HOLE TOLERANCE IS +/- 3 MILS UNLESS OTHERWISE SPECIFIED." at 2190,1890 h50
  text "7) THIS IS A 4 LAYER BOARD." at 2190,1740 h50
  text "8) TRACE WIDTHS IN ARTWORK ARE FINISHED SIZES.  DO NOT DEVIATE" at 2190,1590 h50
  text "WITHOUT PRIOR AUTHORIZATION FROM SCINTERA." at 2340,1440 h50
  text "9) BOW AND TWIST: .75% MAX ALLOWABLE." at 2190,1290 h50
  text "1800mil" at -46.59,1152.5 h50
  text "10) FABRICATE PER IPC-6012 CLASS 2 ( LATEST REVISION ) UNLESS OTHERWISE SPECIFIED." at 2190,1140 h50
  text "11) REMOVE ALL BURRS AND SHARP EDGES." at 2190,990 h50
  text "12) VENDOR SHALL PERFORM FULL NETS LIST TEST - EXTRACT NETS LIST FROM GERBER." at 2190,840 h50
  text "13) FINISHED BOARD SHALL BE RoHS COMPLIANT." at 2190,690 h50
  text "14) COPPER TO THE EDGE BY DESIGN. NO RELIEF." at 2190,540 h50
  text "1000mil" at 1093.41,462.5 h50
  text "15) REMOVE UNUSED PADS." at 2190,390 h50
  text "16) TENT ALL 10 MIL VIAS USING SOLDERMASK ON THE LAYER4." at 2190,240 h50
  text "LAYER STACK UP" at 3190,-210 h65
  text "SCINTERA" at 683,-348 h50
  text "LAYER1 TOP" at 4840,-410 h50
  text "SC1894-DB500A FAB DRILL DRAWING" at 683,-476 h50
  text "FR406 14MIL +/- 1MIL" at 3240,-560 h50
  text "(RDB3.1 REV3)" at 672,-629 h50
  text "LAYER2 GND" at 4840,-710 h50
  text "RF4 PRE-PREG" at 3400,-875 h50
  text "LAYER3 PWR/SIG" at 4840,-1010 h50
  text "42 +/- 4MIL" at 2340,-1110 h50 r90
  text "FR406 14MIL +/- 1MIL" at 3240,-1160 h50
  text "LAYER4 BOTTOM" at 4840,-1310 h50
MECH:
  the board outline again, w2
  text "41" at 75,1050 h35
  text "29" at 795,1050 h35
  text "42" at -910,920 h35
  text "28" at 1050,915 h35
  text "47" at -910,80 h35
  text "14" at 1065,75 h35
  text "1" at 90,-90 h35
  text "13" at 810,-90 h35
